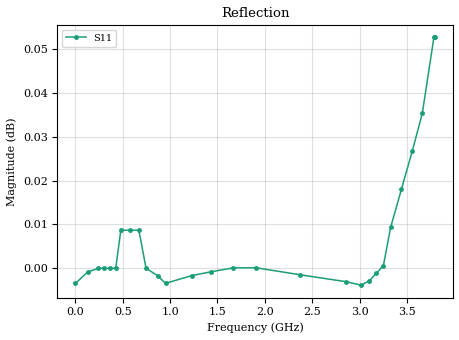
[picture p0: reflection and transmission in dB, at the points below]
! ListType=Lin
!!SAA-2 male short 0.1 to 3800MHz 500 points
# MHz S RI R 50
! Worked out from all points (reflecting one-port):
!   500 points, 100 kHz to 3.8 GHz, reference 50 ohm
!   lowest |S11| = 0.0 dB at 3.016 GHz (marker M1)
!   phase of S11 starts at -180 deg and turns -1 deg over the sweep
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0.1  -0.9996 -0.000886
129.5555  -0.9999 0.000407
243.781  -1 0.00112
304.7012  -1 0.00133
365.6214  -1 0.00143
426.5417  -1 0.00142
479.8469  -1.001 0.00131
578.8423  -1.001 0.00111
670.2226  -1.001 0.00129
746.3729  -1 0.00171
868.2134  -0.9998 0.00271
951.9788  -0.9996 0.00312
1226.12  -0.9998 0.00352
1431.726  -0.9999 0.00394
1667.792  -1 0.00459
1903.858  -1 0.00542
2375.989  -0.9998 0.00747
2855.736  -0.9996 0.00985
3015.652  -0.9995 0.0107
3099.417  -0.9996 0.0111
3175.568  -0.9998 0.0115
3251.718  -1 0.0118
3327.868  -1.001 0.0121
3442.094  -1.002 0.0125
3556.319  -1.003 0.0128
3662.929  -1.004 0.013
3784.77  -1.006 0.0132
3800  -1.006 0.0132
